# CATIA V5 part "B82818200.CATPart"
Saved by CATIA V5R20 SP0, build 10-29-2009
Part number: B82818200
Revision: 5
Definition: design
Nomenclature: B82818200
Source: made
Description: NOT SPECIFIED
Bounding box of the stored display mesh (mm): x -10.833 to 10.833, y -11 to 11, z 0 to 200
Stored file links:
  C:\Users\Raffaele\Desktop\3D X SITO CF\BOLEX\7-PILLAR REF 828\B82818200.CATPart

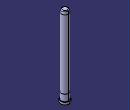
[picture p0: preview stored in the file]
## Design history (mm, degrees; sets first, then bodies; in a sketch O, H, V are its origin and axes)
Body1 "MANIFOLD_SOLID_BREP #450" (main body)
  Solid1: solid without history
